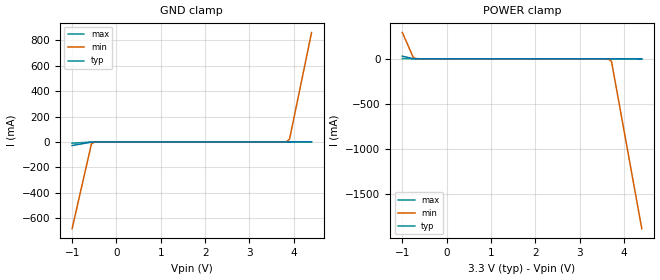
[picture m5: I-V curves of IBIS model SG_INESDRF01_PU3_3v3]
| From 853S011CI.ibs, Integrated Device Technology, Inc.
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[Model] SG_INESDRF01_PU3_3v3
Model_type   Input
Polarity   Non-Inverting
Vinl = 0.8V
Vinh = 2.0V
|   typ   min   max
C_comp   2pF   1.5pF   2.5pF
|   typ   min   max
[Voltage range]   3.3V   3.135V   3.465V
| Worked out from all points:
|   GND clamp passes 1 mA (typ) near -0.53 V on its own axis
|   POWER clamp passes 1 mA (typ) near -0.74 V on its own axis
[GND_clamp]
|Voltage   I (typ)   I (min)   I (max)
-999mV    -28.05mA   -681.9mA   -9.711mA
-564.6mV  -1.569mA   -16.32mA   -752uA
-502.5mV  -540.3uA   -2.825mA   -226.3uA
3.841V    21.14uA    3.749mA    9.297uA
3.904V    50.51uA    23.19mA    10.83uA
4.4V      990.8uA    861.5mA    23.31uA
[Power_clamp]
|Voltage   I (typ)   I (min)   I (max)
-999mV    28.51mA    291.8mA    1.659mA
-750.8mV  1.153mA    13.59mA    131.6uA
-688.7mV  271uA      2.308mA    38.6uA
3.531V    -92.96uA   -256.6uA   -87.2uA
3.655V    -103.3uA   -4.563mA   -90.27uA
3.717V    -147.3uA   -27.95mA   -91.8uA
4.4V      -2.484mA   -1.878A    -109.3uA
